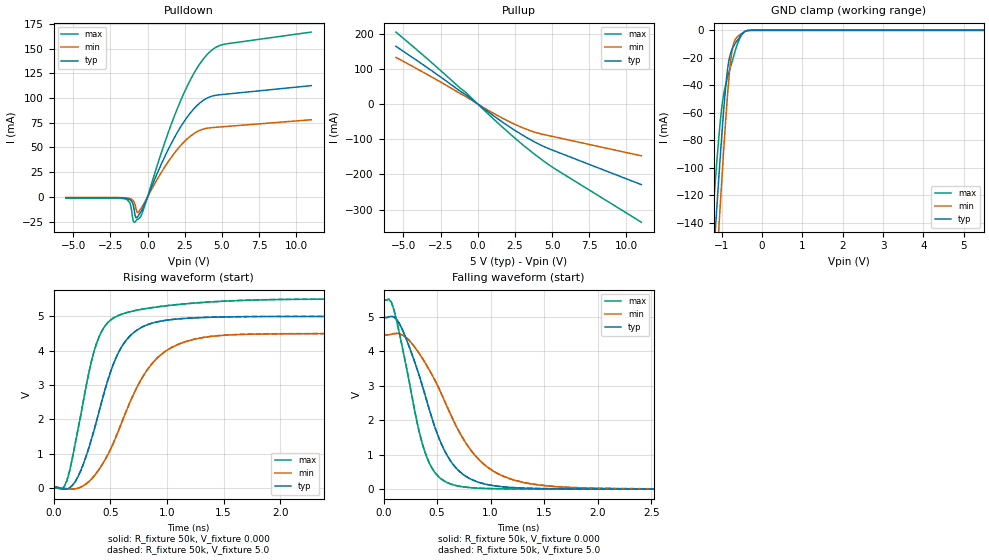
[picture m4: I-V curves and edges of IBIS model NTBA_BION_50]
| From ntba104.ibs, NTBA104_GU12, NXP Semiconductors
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|   Model NTBA_BION_50
[Model]   NTBA_BION_50
Model_type   I/O
Polarity   Non-Inverting
Enable   Active-Low
Vinh  =  3.250 | 0.65*Vcc
Vinl  =  1.750 | 0.35*Vcc
Vmeas =  2.5V  | 0.5*Vcc
Cref  =  15e-12
Rref  =  50k
Vref  =  0V
C_comp   5.8276pF   4.7430pF   8.0332pF
[Model Spec]
| Note: The input and output voltage ratings may be exceeded if the input and
|   output current ratings are observed (please refer to the data sheet)
|   Subparameter   typ   min   max
Vinh   3.250   2.925   3.575
Vinl   1.750   1.575   1.925
| Overshoot
S_overshoot_high   6.5   6.5   6.5   | Static overshoot
S_overshoot_low   -0.5   -0.5   -0.5
D_overshoot_high   7.2   7.2   7.2   | Dynamic overshoot
D_overshoot_low   -1.0   -1.0   -1.0
D_overshoot_time   3n   3n   3n
| Timing Thresholds
Vmeas   2.5   2.25   2.75
|Ambient temperature:   25   85   -40
[Temperature Range]   40   100   -25
[Voltage Range]   5.0   4.5   5.5
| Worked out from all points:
|   slope of the pulldown table from 0 to 0.75 V, typ, clamps not added: 27.4 ohm
|   slope of the pullup table from 0 to 0.75 V, typ, clamps not added: 31.6 ohm
|   GND clamp passes 1 mA (typ) near -0.44 V on its own axis
|   rising waveform, R_fixture 50k, V_fixture 0.000: 20-80 % time 287ps typ, 396ps min, 222ps max; typ from 0 V to 5 V
|   rising waveform, R_fixture 50k, V_fixture 5.0: 20-80 % time 287ps typ, 395ps min, 221ps max; typ from 0.003 V to 5 V
|   falling waveform, R_fixture 50k, V_fixture 0.000: 20-80 % time 334ps typ, 476ps min, 228ps max; typ from 5 V to 0.002 V
|   falling waveform, R_fixture 50k, V_fixture 5.0: 20-80 % time 335ps typ, 476ps min, 228ps max; typ from 5 V to 0.004 V
|Process Range   nominal   slow   fast
[Pulldown]
|   voltage   I(typ)   I(min)   I(max)
-5.5V     -1.007mA   -723.1uA   -1.464mA
-1.52V    -1.383mA   -986.8uA   -2.067mA
-1.2V     -2.763mA   -1.756mA   -5.881mA
-1.08V    -4.342mA   -2.473mA   -13.37mA
-960mV    -8.643mA   -4mA       -24.8mA
-840mV    -18.91mA   -8.136mA   -25.28mA
-600mV    -18.41mA   -15.16mA   -22.21mA
-360mV    -12.65mA   -9.777mA   -16.27mA
2.28V     72.28mA    52.94mA    99.49mA
3.96V     99.71mA    69.41mA    143.5mA
5.16V     103.8mA    71.11mA    154.6mA
11V       112.7mA    78.08mA    166.9mA
[Pullup]
|   voltage   I(typ)   I(min)   I(max)
-5.5V     163.8mA    132.5mA    204.2mA
-840mV    27.31mA    22.08mA    34.24mA
1.25V     -39.04mA   -30.78mA   -49.82mA
3.167V    -92.11mA   -69.84mA   -120.5mA
4.25V     -116.8mA   -84.82mA   -156.2mA
5.167V    -133.2mA   -93.38mA   -183.2mA
11V       -228.9mA   -147.1mA   -335.5mA
[GND_clamp]
|   voltage   I(typ)   I(min)   I(max)
-5.5V     -2.258A    -2.522A    -2.044A
-1.4V     -256mA     -310.3mA   -208.2mA
-1.2V     -162.8mA   -206.8mA   -124.8mA
-1.16V    -144.7mA   -186.6mA   -109.1mA
-1.08V    -109.3mA   -146.7mA   -79.54mA
-1V       -75.83mA   -108.3mA   -55.79mA
-900mV    -39.69mA   -63.54mA   -39.05mA
-840mV    -24.64mA   -40.17mA   -32.26mA
-760mV    -14.81mA   -17.29mA   -24.16mA
-660mV    -9.173mA   -6.28mA    -14.14mA
-420mV    -655.4uA   -781.3uA   -748.7uA
5.5V      0A         0A         0A
[Ramp]
| variable   typ   min   max
dV/dt_r  2.9971E+00/2.8686E-10  2.6963E+00/3.9567E-10  3.2979E+00/2.2151E-10
dV/dt_f  2.9972E+00/3.3447E-10  2.6963E+00/4.7591E-10  3.2982E+00/2.2772E-10
R_load = 50k
[Rising Waveform]
R_fixture   = 50k
V_fixture   = 0.000
V_fixture_min = 0.000
V_fixture_max = 0.000
| time   V(typ)   V(min)   V(max)
0s        1.524nV    12.51nV    69.41pV
119ps     -31.85mV   -26mV      224.1mV
214.3ps   315.3mV    -10.57mV   1.683V
333.3ps   1.401V     252.4mV    3.673V
404.8ps   2.264V     553.3mV    4.425V
523.8ps   3.57V      1.273V     4.937V
619.1ps   4.202V     2.05V      5.078V
904.8ps   4.826V     3.748V     5.266V
1.31ns    4.96V      4.373V     5.398V
5ns       4.995V     4.494V     5.497V
[Rising Waveform]
R_fixture   = 50k
V_fixture   = 5.0
V_fixture_min = 4.5
V_fixture_max = 5.5
| time   V(typ)   V(min)   V(max)
0s        2.601mV    3.112mV    2.151mV
119ps     -29.25mV   -22.92mV   226.4mV
214.3ps   318.2mV    -7.388mV   1.686V
333.3ps   1.404V     256mV      3.676V
404.8ps   2.269V     557.3mV    4.428V
523.8ps   3.574V     1.278V     4.939V
619.1ps   4.206V     2.056V     5.081V
904.8ps   4.83V      3.753V     5.268V
1.31ns    4.963V     4.377V     5.401V
5ns       4.998V     4.497V     5.499V
[Falling Waveform]
R_fixture   = 50k
V_fixture   = 0.000
V_fixture_min = 0.000
V_fixture_max = 0.000
| time   V(typ)   V(min)   V(max)
0s        4.997V     4.497V     5.497V
95.24ps   5.005V     4.516V     5.219V
214.3ps   4.339V     4.392V     3.515V
333.3ps   3.292V     3.936V     1.654V
404.8ps   2.543V     3.58V      915.9mV
523.8ps   1.429V     2.877V     333.6mV
619.1ps   849.1mV    2.216V     158.7mV
928.6ps   163.2mV    745.1mV    22.32mV
1.381ns   23.08mV    153.4mV    5.768mV
5ns       1.599mV    2.603mV    371.7uV
[Falling Waveform]
R_fixture   = 50k
V_fixture   = 5.0
V_fixture_min = 4.5
V_fixture_max = 5.5
| time   V(typ)   V(min)   V(max)
0s        5V         4.5V       5.5V
95.24ps   5.008V     4.519V     5.221V
214.3ps   4.342V     4.395V     3.518V
333.3ps   3.296V     3.94V      1.657V
404.8ps   2.547V     3.584V     918.7mV
500ps     1.622V     3.04V      408.5mV
619.1ps   852.7mV    2.222V     160.8mV
928.6ps   166mV      749.5mV    24.45mV
1.381ns   25.73mV    156.8mV    7.919mV
5ns       4.201mV    5.718mV    2.523mV
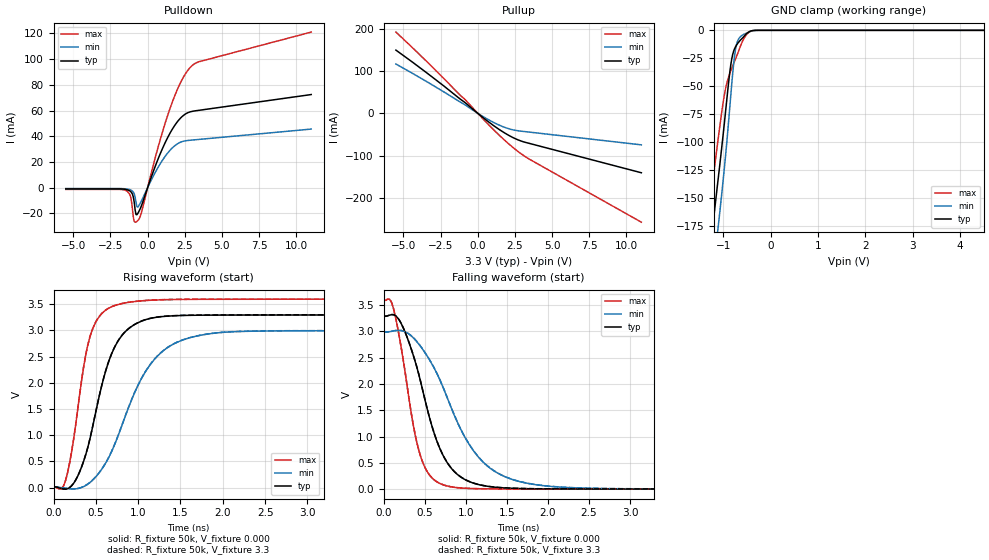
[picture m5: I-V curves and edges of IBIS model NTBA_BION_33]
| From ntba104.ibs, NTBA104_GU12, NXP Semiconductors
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|   Model NTBA_BION_33
[Model]   NTBA_BION_33
Model_type   I/O
Polarity   Non-Inverting
Enable   Active-Low
Vinh  =  2.145 | 0.65*Vcc
Vinl  =  1.116 | 0.35*Vcc
Vmeas =  1.65V | 0.5*Vcc
Cref  =  15e-12
Rref  =  50k
Vref  =  0V
C_comp   6.0003pF   4.9411pF   8.1595pF
[Model Spec]
| Note: The input and output voltage ratings may be exceeded if the input and
|   output current ratings are observed (please refer to the data sheet)
|   Subparameter   typ   min   max
Vinh   2.145   1.950   2.340
Vinl   1.116   1.050   1.260
| Overshoot
S_overshoot_high   6.5   6.5   6.5   | Static overshoot
S_overshoot_low   -0.5   -0.5   -0.5
D_overshoot_high   7.2   7.2   7.2   | Dynamic overshoot
D_overshoot_low   -1.0   -1.0   -1.0
D_overshoot_time   3n   3n   3n
| Timing Thresholds
Vmeas   1.65   1.5   1.8
|Ambient temperature:   25   85   -40
[Temperature Range]   40   100   -25
[Voltage Range]   3.3   3.0   3.6
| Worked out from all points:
|   slope of the pulldown table from 0 to 0.495 V, typ, clamps not added: 30.7 ohm
|   slope of the pullup table from 0 to 0.495 V, typ, clamps not added: 35.4 ohm
|   GND clamp passes 1 mA (typ) near -0.44 V on its own axis
|   rising waveform, R_fixture 50k, V_fixture 0.000: 20-80 % time 323ps typ, 506ps min, 213ps max; typ from 0 V to 3.3 V
|   rising waveform, R_fixture 50k, V_fixture 3.3: 20-80 % time 323ps typ, 505ps min, 213ps max; typ from 0.002 V to 3.3 V
|   falling waveform, R_fixture 50k, V_fixture 0.000: 20-80 % time 376ps typ, 579ps min, 239ps max; typ from 3.3 V to 0.002 V
|   falling waveform, R_fixture 50k, V_fixture 3.3: 20-80 % time 377ps typ, 579ps min, 239ps max; typ from 3.3 V to 0.004 V
|Process Range   nominal   slow   fast
[Pulldown]
|   voltage   I(typ)   I(min)   I(max)
-5.5V     -909uA     -643.4uA   -1.314mA
-1.52V    -1.249mA   -864.7uA   -1.901mA
-1.2V     -2.459mA   -1.516mA   -5.251mA
-1.02V    -5.024mA   -2.624mA   -16.65mA
-900mV    -11.27mA   -4.772mA   -26.18mA
-780mV    -20.84mA   -11.35mA   -26.76mA
-660mV    -20.06mA   -15.08mA   -25.52mA
-420mV    -14.18mA   -10.38mA   -19.44mA
1.394V    40mA       27.59mA    57.84mA
2.132V    53.13mA    34.97mA    79.79mA
2.87V     59.03mA    36.95mA    93.62mA
11V       72.47mA    45.6mA     121.1mA
[Pullup]
|   voltage   I(typ)   I(min)   I(max)
-5.5V     149mA      116.3mA    191.6mA
-3.35V    93.35mA    73.07mA    119.5mA
-1.2V     34.08mA    27mA       43.15mA
-840mV    24.87mA    19.55mA    32.02mA
666.7mV   -18.64mA   -14.08mA   -24.7mA
1.583V    -41.44mA   -30.06mA   -56.35mA
2.333V    -56.68mA   -38.81mA   -79.63mA
2.917V    -65.49mA   -42.23mA   -95.54mA
3.5V      -71.35mA   -44.55mA   -108.9mA
11V       -140.4mA   -74.49mA   -257mA
[GND_clamp]
|   voltage   I(typ)   I(min)   I(max)
-5.5V     -2.257A    -2.522A    -2.041A
-1.4V     -256mA     -310.3mA   -208.2mA
-1.2V     -167.1mA   -212.3mA   -128mA
-1.1V     -130mA     -172.7mA   -94.45mA
-980mV    -84.25mA   -124.5mA   -58.54mA
-860mV    -36.77mA   -67.79mA   -38.41mA
-800mV    -21.46mA   -38.2mA    -31.72mA
-740mV    -14.6mA    -16.87mA   -25.43mA
-660mV    -9.809mA   -6.703mA   -16.68mA
-540mV    -4.319mA   -3.065mA   -5.648mA
-420mV    -672.9uA   -802.2uA   -777.2uA
5.5V      0A         0A         0A
[Ramp]
| variable   typ   min   max
dV/dt_r  1.9776E+00/3.2298E-10  1.7970E+00/5.0577E-10  2.1584E+00/2.1331E-10
dV/dt_f  1.9777E+00/3.7631E-10  1.7970E+00/5.7883E-10  2.1586E+00/2.3911E-10
R_load = 50k
[Rising Waveform]
R_fixture   = 50k
V_fixture   = 0.000
V_fixture_min = 0.000
V_fixture_max = 0.000
| time   V(typ)   V(min)   V(max)
0s        1.167nV    11.72nV    36.72pV
142.9ps   -30.56mV   -15.44mV   136.7mV
214.3ps   33.68mV    -27.26mV   689.2mV
309.5ps   302.3mV    -10.97mV   1.785V
452.4ps   1.086V     126mV      2.988V
690.5ps   2.569V     701.3mV    3.454V
857.1ps   2.991V     1.402V     3.529V
1.095ns   3.209V     2.235V     3.571V
1.548ns   3.287V     2.829V     3.593V
5ns       3.296V     2.995V     3.597V
[Rising Waveform]
R_fixture   = 50k
V_fixture   = 3.3
V_fixture_min = 3.0
V_fixture_max = 3.6
| time   V(typ)   V(min)   V(max)
0s        1.919mV    2.419mV    1.514mV
142.9ps   -28.63mV   -13.04mV   138.3mV
214.3ps   35.72mV    -24.83mV   691mV
309.5ps   304.6mV    -8.44mV    1.788V
452.4ps   1.09V      128.9mV    2.99V
690.5ps   2.572V     705.8mV    3.456V
857.1ps   2.994V     1.408V     3.53V
1.095ns   3.212V     2.24V      3.573V
1.548ns   3.289V     2.832V     3.595V
5ns       3.298V     2.998V     3.599V
[Falling Waveform]
R_fixture   = 50k
V_fixture   = 0.000
V_fixture_min = 0.000
V_fixture_max = 0.000
| time   V(typ)   V(min)   V(max)
0s        3.298V     2.997V     3.598V
71.43ps   3.307V     2.993V     3.612V
142.9ps   3.299V     3.013V     3.281V
357.1ps   2.562V     2.883V     1.248V
452.4ps   2.026V     2.708V     611.3mV
690.5ps   749.7mV    2.056V     104.2mV
857.1ps   338.9mV    1.416V     35.76mV
1.119ns   102.5mV    677.7mV    10.01mV
1.595ns   15.63mV    170mV      4.519mV
5ns       1.6mV      2.33mV     476.5uV
[Falling Waveform]
R_fixture   = 50k
V_fixture   = 3.3
V_fixture_min = 3.0
V_fixture_max = 3.6
| time   V(typ)   V(min)   V(max)
0s        3.3V       3V         3.6V
71.43ps   3.309V     2.995V     3.614V
142.9ps   3.301V     3.016V     3.283V
357.1ps   2.564V     2.886V     1.25V
452.4ps   2.03V      2.711V     613.4mV
690.5ps   752.7mV    2.06V      105.8mV
857.1ps   341.3mV    1.421V     37.31mV
1.119ns   104.6mV    681.7mV    11.53mV
1.595ns   17.58mV    172.9mV    6.035mV
5ns       3.521mV    4.751mV    1.991mV
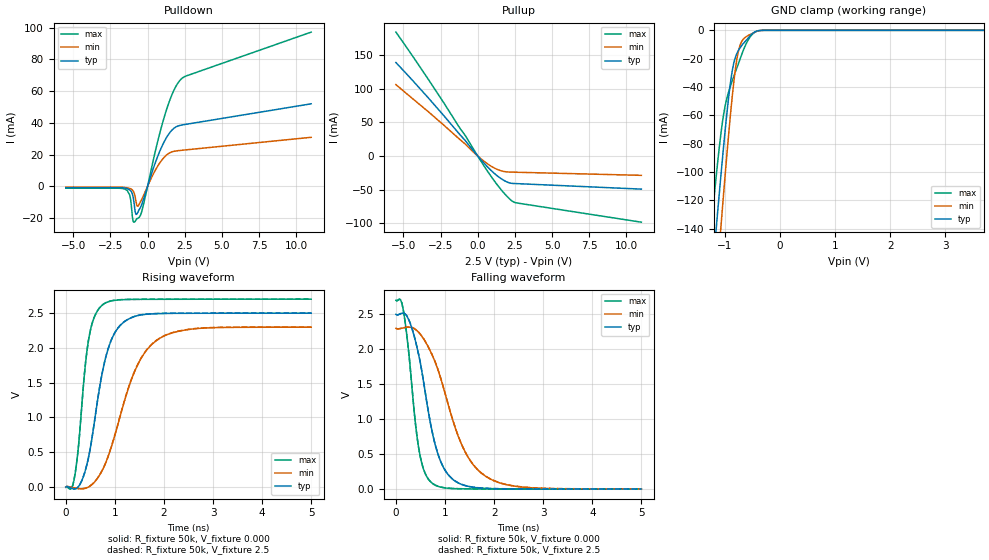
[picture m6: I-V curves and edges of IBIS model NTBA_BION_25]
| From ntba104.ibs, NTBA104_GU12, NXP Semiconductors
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|   Model NTBA_BION_25
[Model]   NTBA_BION_25
Model_type   I/O
Polarity   Non-Inverting
Enable   Active-Low
Vinh  =  1.625 | 0.65*Vcc
Vinl  =  0.875 | 0.35*Vcc
Vmeas =  1.25V | 0.5*Vcc
Cref  =  15e-12
Rref  =  50k
Vref  =  0V
C_comp   6.1047pF   5.0750pF   8.1944pF
[Model Spec]
| Note: The input and output voltage ratings may be exceeded if the input and
|   output current ratings are observed (please refer to the data sheet)
|   Subparameter   typ   min   max
Vinh   1.625   1.495   1.755
Vinl   0.875   0.805   0.945
| Overshoot
S_overshoot_high   6.5   6.5   6.5   | Static overshoot
S_overshoot_low   -0.5   -0.5   -0.5
D_overshoot_high   7.2   7.2   7.2   | Dynamic overshoot
D_overshoot_low   -1.0   -1.0   -1.0
D_overshoot_time   3n   3n   3n
| Timing Thresholds
Vmeas   1.25   1.15   1.35
|Ambient temperature:   25   85   -40
[Temperature Range]   35   95   -35
[Voltage Range]   2.5   2.3   2.7
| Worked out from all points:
|   slope of the pulldown table from 0 to 0.375 V, typ, clamps not added: 34.1 ohm
|   slope of the pullup table from 0 to 0.375 V, typ, clamps not added: 39.5 ohm
|   GND clamp passes 1 mA (typ) near -0.45 V on its own axis
|   rising waveform, R_fixture 50k, V_fixture 0.000: 20-80 % time 385ps typ, 653ps min, 224ps max; typ from 0 V to 2.5 V
|   rising waveform, R_fixture 50k, V_fixture 2.5: 20-80 % time 385ps typ, 652ps min, 224ps max; typ from 0.002 V to 2.5 V
|   falling waveform, R_fixture 50k, V_fixture 0.000: 20-80 % time 418ps typ, 681ps min, 247ps max; typ from 2.5 V to 0.002 V
|   falling waveform, R_fixture 50k, V_fixture 2.5: 20-80 % time 419ps typ, 682ps min, 247ps max; typ from 2.5 V to 0.003 V
|Process Range   nominal   slow   fast
[Pulldown]
|   voltage   I(typ)   I(min)   I(max)
-5.5V     -854.5uA   -597.8uA   -1.251mA
-1.52V    -1.17mA    -794.1uA   -1.852mA
-1.2V     -2.314mA   -1.383mA   -5.627mA
-1.02V    -4.942mA   -2.404mA   -19.59mA
-900mV    -11.38mA   -4.341mA   -22.67mA
-780mV    -17.78mA   -9.662mA   -21.21mA
-660mV    -16.59mA   -12.64mA   -20.24mA
-360mV    -10.58mA   -7.669mA   -14.72mA
1.024V    26.36mA    17.29mA    40.56mA
1.6V      35.04mA    21.56mA    56.89mA
2.176V    38.36mA    22.56mA    66.78mA
11V       51.99mA    30.86mA    97.21mA
[Pullup]
|   voltage   I(typ)   I(min)   I(max)
-5.5V     138.9mA    106.1mA    184.1mA
-4.425V   113.4mA    86.06mA    150mA
-2.275V   59.83mA    45.72mA    78.82mA
-1.2V     31.78mA    24.51mA    41.29mA
-780mV    21.36mA    16.42mA    28.34mA
500mV     -12.52mA   -9.087mA   -17.34mA
1V        -23.55mA   -16.47mA   -33.48mA
1.5V      -32.59mA   -21.48mA   -48.09mA
1.917V    -38.07mA   -23.49mA   -58.74mA
2.25V     -40.47mA   -23.94mA   -65.92mA
2.667V    -41.07mA   -24.16mA   -69.92mA
11V       -49.2mA    -28.72mA   -98.33mA
[GND_clamp]
|   voltage   I(typ)   I(min)   I(max)
-5.5V     -2.254A    -2.519A    -2.036A
-1.4V     -253mA     -307.1mA   -203.2mA
-1.2V     -160mA     -203.6mA   -120.2mA
-1.16V    -141.9mA   -183.4mA   -104.6mA
-1.08V    -106.6mA   -143.6mA   -76.02mA
-1.06V    -98mA      -133.8mA   -69.76mA
-900mV    -37.81mA   -60.73mA   -39.71mA
-840mV    -23.69mA   -37.76mA   -32.84mA
-760mV    -14.7mA    -15.96mA   -24.34mA
-660mV    -9.154mA   -6.098mA   -13.73mA
-420mV    -585.7uA   -699.8uA   -577.7uA
5.5V      0A         0A         0A
[Ramp]
| variable   typ   min   max
dV/dt_r  1.4979E+00/3.8499E-10  1.3773E+00/6.5291E-10  1.6186E+00/2.2380E-10
dV/dt_f  1.4979E+00/4.1833E-10  1.3773E+00/6.8075E-10  1.6188E+00/2.4721E-10
R_load = 50k
[Rising Waveform]
R_fixture   = 50k
V_fixture   = 0.000
V_fixture_min = 0.000
V_fixture_max = 0.000
| time   V(typ)   V(min)   V(max)
0s        710.1pV    8.761nV    8.576pV
119ps     -17.55mV   -4.403mV   -13.6mV
190.5ps   -25.35mV   -13.3mV    194.2mV
381ps     200mV      -19.18mV   1.632V
523.8ps   660.1mV    31.72mV    2.317V
761.9ps   1.706V     267.6mV    2.623V
1.119ns   2.328V     1.047V     2.689V
1.452ns   2.46V      1.738V     2.695V
1.833ns   2.489V     2.098V     2.696V
5ns       2.497V     2.295V     2.698V
[Rising Waveform]
R_fixture   = 50k
V_fixture   = 2.5
V_fixture_min = 2.3
V_fixture_max = 2.7
| time   V(typ)   V(min)   V(max)
0s        1.603mV    2.116mV    1.194mV
119ps     -15.95mV   -2.294mV   -12.38mV
190.5ps   -23.71mV   -11.19mV   195.6mV
381ps     202mV      -16.94mV   1.634V
523.8ps   663.1mV    34.19mV    2.319V
761.9ps   1.709V     270.9mV    2.625V
1.119ns   2.331V     1.053V     2.691V
1.452ns   2.462V     1.743V     2.696V
1.833ns   2.491V     2.101V     2.697V
5ns       2.498V     2.298V     2.699V
[Falling Waveform]
R_fixture   = 50k
V_fixture   = 0.000
V_fixture_min = 0.000
V_fixture_max = 0.000
| time   V(typ)   V(min)   V(max)
0s        2.498V     2.298V     2.699V
142.9ps   2.515V     2.303V     2.589V
333.3ps   2.281V     2.306V     1.403V
500ps     1.794V     2.211V     451.5mV
738.1ps   820.6mV    1.917V     85.88mV
904.8ps   408.1mV    1.601V     30.95mV
1.095ns   182.6mV    1.134V     11.92mV
1.429ns   47.96mV    508.5mV    4.882mV
1.833ns   11.83mV    181.5mV    3.428mV
5ns       1.576mV    2.201mV    544.1uV
[Falling Waveform]
R_fixture   = 50k
V_fixture   = 2.5
V_fixture_min = 2.3
V_fixture_max = 2.7
| time   V(typ)   V(min)   V(max)
0s        2.5V       2.3V       2.7V
142.9ps   2.518V     2.305V     2.59V
333.3ps   2.283V     2.309V     1.406V
500ps     1.796V     2.213V     453.2mV
738.1ps   823.8mV    1.92V      87.29mV
904.8ps   410.7mV    1.605V     32.21mV
1.095ns   184.7mV    1.139V     13.13mV
1.429ns   49.74mV    512.4mV    6.079mV
1.833ns   13.47mV    184.3mV    4.623mV
5ns       3.181mV    4.321mV    1.738mV
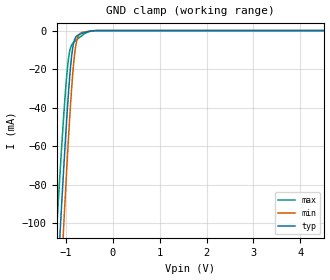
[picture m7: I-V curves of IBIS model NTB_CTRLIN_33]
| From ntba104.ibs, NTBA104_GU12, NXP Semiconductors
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|   Model NTB_CTRLIN_33
[Model]   NTB_CTRLIN_33
Model_type   Input
Vinh  =  2.145 | 0.65*Vcc
Vinl  =  1.116 | 0.35*Vcc
C_comp   0.7965pF   0.5744pF   1.1799pF
[Model Spec]
| Note: The input and output voltage ratings may be exceeded if the input and
|   output current ratings are observed (please refer to the data sheet)
|   Subparameter   typ   min   max
Vinh   2.145   1.950   2.340
Vinl   1.116   1.050   1.260
| Overshoot
S_overshoot_high   6.5   6.5   6.5   | Static overshoot
S_overshoot_low   -0.5   -0.5   -0.5
D_overshoot_high   7.2   7.2   7.2   | Dynamic overshoot
D_overshoot_low   -1.0   -1.0   -1.0
D_overshoot_time   3n   3n   3n
|Ambient temperature:   25   85   -40
[Temperature Range]   40   100   -25
[Voltage Range]   3.3   3.0   3.6
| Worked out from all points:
|   GND clamp passes 1 mA (typ) near -0.59 V on its own axis
|Process Range   nominal   slow   fast
[GND_clamp]
|   voltage   I(typ)   I(min)   I(max)
-5.5V     -2.251A    -2.518A    -2.029A
-1.2V     -138.9mA   -176.5mA   -104.2mA
-1.12V    -103mA     -136.7mA   -71.91mA
-1.06V    -77.12mA   -107.7mA   -49.02mA
-1.04V    -68.75mA   -98.28mA   -41.84mA
-960mV    -37.56mA   -62.2mA    -17.73mA
-920mV    -24.25mA   -45.68mA   -10.75mA
-860mV    -9.822mA   -24.24mA   -6.829mA
-780mV    -3.129mA   -6.492mA   -4.877mA
-660mV    -1.506mA   -1.037mA   -2.623mA
-340mV    -12.74uA   -18.04uA   -10.63uA
5.5V      0A         0A         0A
